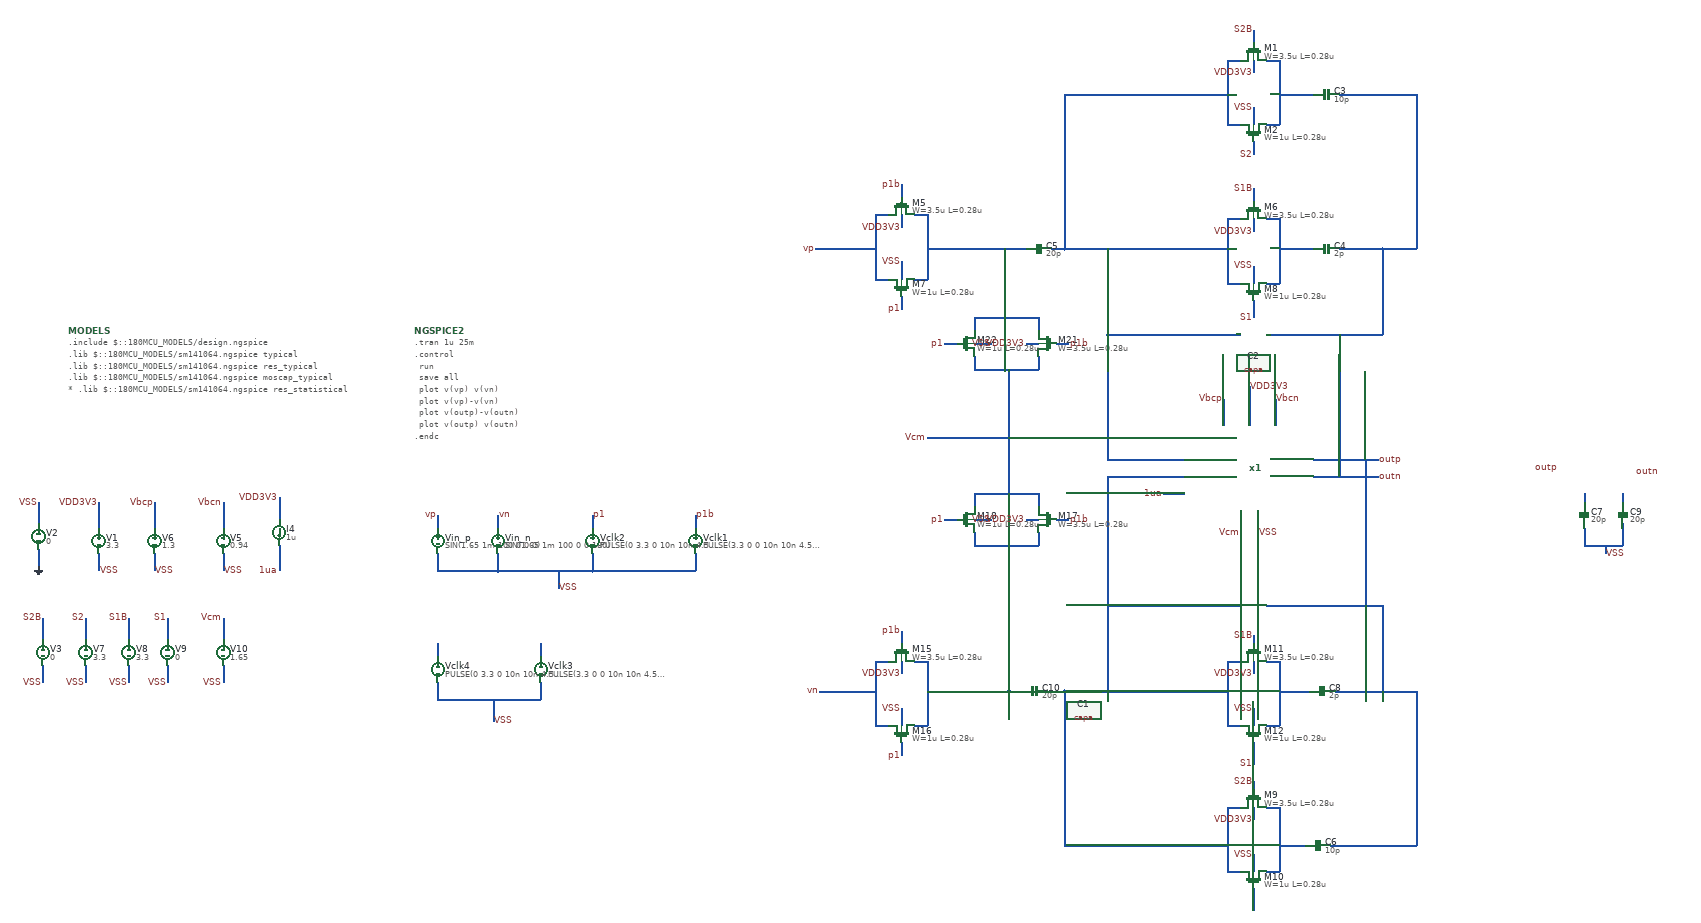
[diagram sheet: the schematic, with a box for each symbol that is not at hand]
v {xschem version=3.4.8RC file_version=1.3}
G {}
K {}
V {}
S {}
F {}
E {}
N 1350 -1840 1350 -1790 {lab=VDD3V3}
N 1350 -1730 1350 -1670 {lab=1ua}
N 1220 -1710 1220 -1670 {lab=VSS}
N 1220 -1830 1220 -1770 {lab=Vbcn}
N 1060 -1710 1060 -1670 {lab=VSS}
N 1060 -1830 1060 -1770 {lab=Vbcp}
N 930 -1710 930 -1670 {lab=VSS}
N 930 -1830 930 -1770 {lab=VDD3V3}
N 790 -1720 790 -1690 {lab=0}
N 790 -1690 790 -1680 {lab=0}
N 790 -1830 790 -1780 {lab=VSS}
N 3630 -1810 3630 -1760 {lab=VSS}
N 3190 -2420 3320 -2420 {lab=#net1}
N 3380 -2420 3560 -2420 {lab=#net1}
N 3180 -2420 3190 -2420 {lab=#net1}
N 3280 -2220 3590 -2220 {lab=#net1}
N 3280 -2420 3280 -2220 {lab=#net1}
N 3650 -2220 3920 -2220 {lab=outn}
N 3920 -2420 3920 -2220 {lab=outn}
N 3190 -2780 3320 -2780 {lab=#net1}
N 3180 -2780 3190 -2780 {lab=#net1}
N 3180 -2780 3180 -2420 {lab=#net1}
N 4000 -2780 4000 -2420 {lab=outn}
N 3760 -1930 3910 -1930 {lab=outp}
N 2610 -2420 2740 -2420 {lab=vp}
N 2600 -2420 2610 -2420 {lab=vp}
N 3190 -1390 3320 -1390 {lab=#net2}
N 3380 -1390 3560 -1390 {lab=#net2}
N 3180 -1390 3190 -1390 {lab=#net2}
N 3280 -1590 3590 -1590 {lab=#net2}
N 3280 -1590 3280 -1390 {lab=#net2}
N 3650 -1590 3920 -1590 {lab=outp}
N 3920 -1590 3920 -1390 {lab=outp}
N 3190 -1030 3320 -1030 {lab=#net2}
N 3380 -1030 3560 -1030 {lab=#net2}
N 3180 -1030 3190 -1030 {lab=#net2}
N 3180 -1390 3180 -1030 {lab=#net2}
N 4000 -1390 4000 -1030 {lab=outp}
N 2610 -1390 2740 -1390 {lab=vn}
N 3760 -1890 3910 -1890 {lab=outn}
N 2860 -2420 2930 -2420 {lab=#net3}
N 3040 -2420 3040 -2260 {lab=#net3}
N 3050 -1730 3050 -1570 {lab=#net4}
N 3050 -2140 3050 -1930 {lab=Vcm}
N 3050 -1930 3050 -1850 {lab=Vcm}
N 2860 -1980 3050 -1980 {lab=Vcm}
N 2860 -1390 2920 -1390 {lab=#net4}
N 3050 -1570 3050 -1390 {lab=#net4}
N 3280 -2220 3280 -1930 {lab=#net1}
N 3320 -2780 3560 -2780 {lab=#net1}
N 3680 -2780 3760 -2780 {lab=#net5}
N 3820 -2780 4000 -2780 {lab=outn}
N 3680 -2420 3760 -2420 {lab=#net6}
N 3820 -2420 3920 -2420 {lab=outn}
N 3920 -2420 4000 -2420 {lab=outn}
N 3320 -2420 3380 -2420 {lab=#net1}
N 3820 -2220 3820 -1890 {lab=outn}
N 3880 -1920 3880 -1590 {lab=outp}
N 2930 -2420 3050 -2420 {lab=#net3}
N 3050 -2420 3090 -2420 {lab=#net3}
N 3150 -2420 3180 -2420 {lab=#net1}
N 3140 -1390 3180 -1390 {lab=#net2}
N 3050 -1390 3080 -1390 {lab=#net4}
N 2920 -1390 3050 -1390 {lab=#net4}
N 3560 -2860 3590 -2860 {lab=#net1}
N 3560 -2860 3560 -2710 {lab=#net1}
N 3560 -2710 3590 -2710 {lab=#net1}
N 3650 -2860 3680 -2860 {lab=#net5}
N 3680 -2860 3680 -2710 {lab=#net5}
N 3650 -2710 3680 -2710 {lab=#net5}
N 3280 -1890 3280 -1590 {lab=#net2}
N 3880 -1930 3880 -1920 {lab=outp}
N 3320 -1390 3380 -1390 {lab=#net2}
N 3810 -1390 4000 -1390 {lab=outp}
N 3680 -1390 3750 -1390 {lab=#net7}
N 3800 -1030 3990 -1030 {lab=outp}
N 3990 -1030 4000 -1030 {lab=outp}
N 3320 -1030 3380 -1030 {lab=#net2}
N 3620 -2860 3620 -2830 {lab=VDD3V3}
N 3620 -2750 3620 -2710 {lab=VSS}
N 3560 -2490 3590 -2490 {lab=#net1}
N 3560 -2490 3560 -2340 {lab=#net1}
N 3560 -2340 3590 -2340 {lab=#net1}
N 3650 -2490 3680 -2490 {lab=#net6}
N 3680 -2490 3680 -2340 {lab=#net6}
N 3650 -2340 3680 -2340 {lab=#net6}
N 3620 -2490 3620 -2460 {lab=VDD3V3}
N 3620 -2380 3620 -2340 {lab=VSS}
N 3560 -1120 3590 -1120 {lab=#net2}
N 3560 -1120 3560 -970 {lab=#net2}
N 3560 -970 3590 -970 {lab=#net2}
N 3650 -1120 3680 -1120 {lab=#net8}
N 3680 -1120 3680 -970 {lab=#net8}
N 3650 -970 3680 -970 {lab=#net8}
N 3620 -1120 3620 -1090 {lab=VDD3V3}
N 3620 -1010 3620 -970 {lab=VSS}
N 3560 -1460 3590 -1460 {lab=#net2}
N 3560 -1460 3560 -1310 {lab=#net2}
N 3560 -1310 3590 -1310 {lab=#net2}
N 3650 -1460 3680 -1460 {lab=#net7}
N 3680 -1460 3680 -1310 {lab=#net7}
N 3650 -1310 3680 -1310 {lab=#net7}
N 3620 -1460 3620 -1430 {lab=VDD3V3}
N 3620 -1350 3620 -1310 {lab=VSS}
N 2740 -2500 2770 -2500 {lab=vp}
N 2740 -2500 2740 -2350 {lab=vp}
N 2740 -2350 2770 -2350 {lab=vp}
N 2830 -2500 2860 -2500 {lab=#net3}
N 2860 -2500 2860 -2350 {lab=#net3}
N 2830 -2350 2860 -2350 {lab=#net3}
N 2800 -2500 2800 -2470 {lab=VDD3V3}
N 2800 -2390 2800 -2350 {lab=VSS}
N 2740 -1460 2770 -1460 {lab=vn}
N 2740 -1460 2740 -1310 {lab=vn}
N 2740 -1310 2770 -1310 {lab=vn}
N 2830 -1460 2860 -1460 {lab=#net4}
N 2860 -1460 2860 -1310 {lab=#net4}
N 2830 -1310 2860 -1310 {lab=#net4}
N 2800 -1460 2800 -1430 {lab=VDD3V3}
N 2800 -1350 2800 -1310 {lab=VSS}
N 3120 -2260 3120 -2230 {lab=#net3}
N 2970 -2260 3120 -2260 {lab=#net3}
N 2970 -2260 2970 -2230 {lab=#net3}
N 3120 -2170 3120 -2140 {lab=Vcm}
N 2970 -2140 3120 -2140 {lab=Vcm}
N 2970 -2170 2970 -2140 {lab=Vcm}
N 3090 -2200 3120 -2200 {lab=VDD3V3}
N 2970 -2200 3010 -2200 {lab=VSS}
N 3120 -1850 3120 -1820 {lab=Vcm}
N 2970 -1850 3120 -1850 {lab=Vcm}
N 2970 -1850 2970 -1820 {lab=Vcm}
N 3120 -1760 3120 -1730 {lab=#net4}
N 2970 -1730 3120 -1730 {lab=#net4}
N 2970 -1760 2970 -1730 {lab=#net4}
N 3090 -1790 3120 -1790 {lab=VDD3V3}
N 2970 -1790 3010 -1790 {lab=VSS}
N 1720 -1710 1720 -1670 {lab=VSS}
N 1860 -1710 1860 -1670 {lab=VSS}
N 1720 -1670 1860 -1670 {lab=VSS}
N 2000 -1670 2000 -1630 {lab=VSS}
N 1720 -1800 1720 -1770 {lab=vp}
N 1860 -1800 1860 -1770 {lab=vn}
N 3620 -2930 3620 -2900 {lab=S2B}
N 3620 -2670 3620 -2640 {lab=S2}
N 3620 -2560 3620 -2530 {lab=S1B}
N 3620 -2300 3620 -2270 {lab=S1}
N 3620 -2270 3620 -2260 {lab=S1}
N 3620 -1520 3620 -1500 {lab=S1B}
N 3620 -1270 3620 -1220 {lab=S1}
N 3620 -1180 3620 -1160 {lab=S2B}
N 3620 -930 3620 -880 {lab=#net9}
N 3680 -1030 3740 -1030 {lab=#net8}
N 2800 -2570 2800 -2540 {lab=p1b}
N 2800 -2310 2800 -2280 {lab=p1}
N 2800 -1530 2800 -1500 {lab=p1b}
N 2800 -1270 2800 -1240 {lab=p1}
N 2900 -1790 2930 -1790 {lab=p1}
N 3160 -1790 3190 -1790 {lab=p1b}
N 3160 -2200 3190 -2200 {lab=p1b}
N 2900 -2200 2930 -2200 {lab=p1}
N 2080 -1710 2080 -1670 {lab=VSS}
N 2080 -1800 2080 -1770 {lab=p1}
N 1860 -1670 2080 -1670 {lab=VSS}
N 2320 -1710 2320 -1670 {lab=VSS}
N 2320 -1800 2320 -1770 {lab=p1b}
N 2080 -1670 2320 -1670 {lab=VSS}
N 800 -1450 800 -1420 {lab=VSS}
N 800 -1420 800 -1410 {lab=VSS}
N 800 -1560 800 -1510 {lab=S2B}
N 900 -1450 900 -1420 {lab=VSS}
N 900 -1420 900 -1410 {lab=VSS}
N 900 -1560 900 -1510 {lab=S2}
N 1000 -1450 1000 -1420 {lab=VSS}
N 1000 -1420 1000 -1410 {lab=VSS}
N 1000 -1560 1000 -1510 {lab=S1B}
N 1090 -1450 1090 -1420 {lab=VSS}
N 1090 -1420 1090 -1410 {lab=VSS}
N 1090 -1560 1090 -1510 {lab=S1}
N 3280 -1930 3460 -1930 {lab=#net1}
N 3280 -1890 3460 -1890 {lab=#net2}
N 3410 -1850 3460 -1850 {lab=1ua}
N 3610 -2100 3610 -2010 {lab=VDD3V3}
N 3670 -2070 3670 -2010 {lab=Vbcn}
N 3590 -1810 3590 -1760 {lab=Vcm}
N 1220 -1450 1220 -1420 {lab=VSS}
N 1220 -1420 1220 -1410 {lab=VSS}
N 1220 -1560 1220 -1510 {lab=Vcm}
N 4390 -1850 4390 -1830 {lab=#net10}
N 4480 -1850 4480 -1830 {lab=#net11}
N 4390 -1770 4390 -1730 {lab=VSS}
N 4390 -1730 4480 -1730 {lab=VSS}
N 4480 -1780 4480 -1730 {lab=VSS}
N 4440 -1730 4440 -1710 {lab=VSS}
N 3550 -2070 3550 -2010 {lab=Vbcp}
N 1720 -1410 1720 -1370 {lab=VSS}
N 1720 -1500 1720 -1470 {lab=#net12}
N 1960 -1410 1960 -1370 {lab=VSS}
N 1960 -1500 1960 -1470 {lab=#net13}
N 1720 -1370 1960 -1370 {lab=VSS}
N 1850 -1370 1850 -1320 {lab=VSS}
C {isource.sym} 1350 -1760 0 0 {name=I4 value=1u}
C {lab_pin.sym} 1350 -1670 0 0 {name=p61 sig_type=std_logic lab=1ua}
C {vsource.sym} 1220 -1740 0 0 {name=V5 value=0.94 savecurrent=false}
C {vsource.sym} 1060 -1740 0 0 {name=V6 value=1.3 savecurrent=false}
C {lab_pin.sym} 1060 -1830 0 0 {name=p24 sig_type=std_logic lab=Vbcp}
C {lab_pin.sym} 1220 -1830 0 0 {name=p12 sig_type=std_logic lab=Vbcn}
C {lab_wire.sym} 1060 -1670 0 1 {name=p32 sig_type=std_logic lab=VSS}
C {lab_wire.sym} 1220 -1670 0 1 {name=p43 sig_type=std_logic lab=VSS}
C {vsource.sym} 930 -1740 0 0 {name=V1 value=3.3 savecurrent=false}
C {lab_pin.sym} 930 -1830 0 0 {name=p5 sig_type=std_logic lab=VDD3V3}
C {lab_wire.sym} 790 -1830 0 0 {name=p15 sig_type=std_logic lab=VSS}
C {vsource.sym} 790 -1750 0 0 {name=V2 value=0 savecurrent=false}
C {lab_wire.sym} 930 -1670 0 1 {name=p42 sig_type=std_logic lab=VSS}
C {gnd.sym} 790 -1680 0 0 {name=l1 lab=0}
C {lab_pin.sym} 1350 -1840 0 0 {name=p1 sig_type=std_logic lab=VDD3V3}
C {lab_pin.sym} 3410 -1850 0 0 {name=p2 sig_type=std_logic lab=1ua}
C {lab_wire.sym} 3630 -1760 0 1 {name=p3 sig_type=std_logic lab=VSS}
C {lab_pin.sym} 3610 -2100 0 1 {name=p4 sig_type=std_logic lab=VDD3V3}
C {capa.sym} 3790 -2780 3 1 {name=C3
m=1
value=10p
footprint=1206
device="ceramic capacitor"}
C {capa.sym} 3120 -2420 1 0 {name=C5
m=1
value=20p
footprint=1206
device="ceramic capacitor"}
C {capa.sym} 3110 -1390 1 1 {name=C10
m=1
value=20p
footprint=1206
device="ceramic capacitor"}
C {lab_pin.sym} 3910 -1930 0 1 {name=p11 sig_type=std_logic lab=outp}
C {lab_pin.sym} 3910 -1890 0 1 {name=p13 sig_type=std_logic lab=outn}
C {capa.sym} 3790 -2420 3 1 {name=C4
m=1
value=2p
footprint=1206
device="ceramic capacitor"}
C {lab_wire.sym} 2600 -2420 0 0 {name=p14 sig_type=std_logic lab=vp}
C {lab_wire.sym} 2610 -1390 0 0 {name=p16 sig_type=std_logic lab=vn}
C {symbols/pfet_03v3.sym} 3620 -2880 1 0 {name=M1
L=0.28u
W=3.5u
nf=1
m=1
ad="'int((nf+1)/2) * W/nf * 0.18u'"
pd="'2*int((nf+1)/2) * (W/nf + 0.18u)'"
as="'int((nf+2)/2) * W/nf * 0.18u'"
ps="'2*int((nf+2)/2) * (W/nf + 0.18u)'"
nrd="'0.18u / W'" nrs="'0.18u / W'"
sa=0 sb=0 sd=0
model=pfet_03v3
spiceprefix=X
}
C {symbols/nfet_03v3.sym} 3620 -2690 1 1 {name=M2
L=0.28u
W=1u
nf=1
m=1
ad="'int((nf+1)/2) * W/nf * 0.18u'"
pd="'2*int((nf+1)/2) * (W/nf + 0.18u)'"
as="'int((nf+2)/2) * W/nf * 0.18u'"
ps="'2*int((nf+2)/2) * (W/nf + 0.18u)'"
nrd="'0.18u / W'" nrs="'0.18u / W'"
sa=0 sb=0 sd=0
model=nfet_03v3
spiceprefix=X
}
C {capa.sym} 3520 -1550 3 1 {name=C1
m=1
value=1p
footprint=1206
device="ceramic capacitor"}
C {capa.sym} 3770 -1030 3 1 {name=C6
m=1
value=10p
footprint=1206
device="ceramic capacitor"}
C {lab_pin.sym} 3620 -2830 0 0 {name=p17 sig_type=std_logic lab=VDD3V3}
C {lab_wire.sym} 3620 -2750 0 0 {name=p18 sig_type=std_logic lab=VSS}
C {symbols/pfet_03v3.sym} 3620 -2510 1 0 {name=M6
L=0.28u
W=3.5u
nf=1
m=1
ad="'int((nf+1)/2) * W/nf * 0.18u'"
pd="'2*int((nf+1)/2) * (W/nf + 0.18u)'"
as="'int((nf+2)/2) * W/nf * 0.18u'"
ps="'2*int((nf+2)/2) * (W/nf + 0.18u)'"
nrd="'0.18u / W'" nrs="'0.18u / W'"
sa=0 sb=0 sd=0
model=pfet_03v3
spiceprefix=X
}
C {symbols/nfet_03v3.sym} 3620 -2320 1 1 {name=M8
L=0.28u
W=1u
nf=1
m=1
ad="'int((nf+1)/2) * W/nf * 0.18u'"
pd="'2*int((nf+1)/2) * (W/nf + 0.18u)'"
as="'int((nf+2)/2) * W/nf * 0.18u'"
ps="'2*int((nf+2)/2) * (W/nf + 0.18u)'"
nrd="'0.18u / W'" nrs="'0.18u / W'"
sa=0 sb=0 sd=0
model=nfet_03v3
spiceprefix=X
}
C {lab_pin.sym} 3620 -2460 0 0 {name=p21 sig_type=std_logic lab=VDD3V3}
C {lab_wire.sym} 3620 -2380 0 0 {name=p22 sig_type=std_logic lab=VSS}
C {symbols/pfet_03v3.sym} 3620 -1140 1 0 {name=M9
L=0.28u
W=3.5u
nf=1
m=1
ad="'int((nf+1)/2) * W/nf * 0.18u'"
pd="'2*int((nf+1)/2) * (W/nf + 0.18u)'"
as="'int((nf+2)/2) * W/nf * 0.18u'"
ps="'2*int((nf+2)/2) * (W/nf + 0.18u)'"
nrd="'0.18u / W'" nrs="'0.18u / W'"
sa=0 sb=0 sd=0
model=pfet_03v3
spiceprefix=X
}
C {symbols/nfet_03v3.sym} 3620 -950 1 1 {name=M10
L=0.28u
W=1u
nf=1
m=1
ad="'int((nf+1)/2) * W/nf * 0.18u'"
pd="'2*int((nf+1)/2) * (W/nf + 0.18u)'"
as="'int((nf+2)/2) * W/nf * 0.18u'"
ps="'2*int((nf+2)/2) * (W/nf + 0.18u)'"
nrd="'0.18u / W'" nrs="'0.18u / W'"
sa=0 sb=0 sd=0
model=nfet_03v3
spiceprefix=X
}
C {lab_pin.sym} 3620 -1090 0 0 {name=p23 sig_type=std_logic lab=VDD3V3}
C {lab_wire.sym} 3620 -1010 0 0 {name=p25 sig_type=std_logic lab=VSS}
C {symbols/pfet_03v3.sym} 3620 -1480 1 0 {name=M11
L=0.28u
W=3.5u
nf=1
m=1
ad="'int((nf+1)/2) * W/nf * 0.18u'"
pd="'2*int((nf+1)/2) * (W/nf + 0.18u)'"
as="'int((nf+2)/2) * W/nf * 0.18u'"
ps="'2*int((nf+2)/2) * (W/nf + 0.18u)'"
nrd="'0.18u / W'" nrs="'0.18u / W'"
sa=0 sb=0 sd=0
model=pfet_03v3
spiceprefix=X
}
C {symbols/nfet_03v3.sym} 3620 -1290 1 1 {name=M12
L=0.28u
W=1u
nf=1
m=1
ad="'int((nf+1)/2) * W/nf * 0.18u'"
pd="'2*int((nf+1)/2) * (W/nf + 0.18u)'"
as="'int((nf+2)/2) * W/nf * 0.18u'"
ps="'2*int((nf+2)/2) * (W/nf + 0.18u)'"
nrd="'0.18u / W'" nrs="'0.18u / W'"
sa=0 sb=0 sd=0
model=nfet_03v3
spiceprefix=X
}
C {lab_pin.sym} 3620 -1430 0 0 {name=p26 sig_type=std_logic lab=VDD3V3}
C {lab_wire.sym} 3620 -1350 0 0 {name=p27 sig_type=std_logic lab=VSS}
C {symbols/pfet_03v3.sym} 2800 -2520 1 0 {name=M5
L=0.28u
W=3.5u
nf=1
m=1
ad="'int((nf+1)/2) * W/nf * 0.18u'"
pd="'2*int((nf+1)/2) * (W/nf + 0.18u)'"
as="'int((nf+2)/2) * W/nf * 0.18u'"
ps="'2*int((nf+2)/2) * (W/nf + 0.18u)'"
nrd="'0.18u / W'" nrs="'0.18u / W'"
sa=0 sb=0 sd=0
model=pfet_03v3
spiceprefix=X
}
C {symbols/nfet_03v3.sym} 2800 -2330 1 1 {name=M7
L=0.28u
W=1u
nf=1
m=1
ad="'int((nf+1)/2) * W/nf * 0.18u'"
pd="'2*int((nf+1)/2) * (W/nf + 0.18u)'"
as="'int((nf+2)/2) * W/nf * 0.18u'"
ps="'2*int((nf+2)/2) * (W/nf + 0.18u)'"
nrd="'0.18u / W'" nrs="'0.18u / W'"
sa=0 sb=0 sd=0
model=nfet_03v3
spiceprefix=X
}
C {lab_pin.sym} 2800 -2470 0 0 {name=p30 sig_type=std_logic lab=VDD3V3}
C {lab_wire.sym} 2800 -2390 0 0 {name=p31 sig_type=std_logic lab=VSS}
C {symbols/pfet_03v3.sym} 2800 -1480 1 0 {name=M15
L=0.28u
W=3.5u
nf=1
m=1
ad="'int((nf+1)/2) * W/nf * 0.18u'"
pd="'2*int((nf+1)/2) * (W/nf + 0.18u)'"
as="'int((nf+2)/2) * W/nf * 0.18u'"
ps="'2*int((nf+2)/2) * (W/nf + 0.18u)'"
nrd="'0.18u / W'" nrs="'0.18u / W'"
sa=0 sb=0 sd=0
model=pfet_03v3
spiceprefix=X
}
C {symbols/nfet_03v3.sym} 2800 -1290 1 1 {name=M16
L=0.28u
W=1u
nf=1
m=1
ad="'int((nf+1)/2) * W/nf * 0.18u'"
pd="'2*int((nf+1)/2) * (W/nf + 0.18u)'"
as="'int((nf+2)/2) * W/nf * 0.18u'"
ps="'2*int((nf+2)/2) * (W/nf + 0.18u)'"
nrd="'0.18u / W'" nrs="'0.18u / W'"
sa=0 sb=0 sd=0
model=nfet_03v3
spiceprefix=X
}
C {lab_pin.sym} 2800 -1430 0 0 {name=p33 sig_type=std_logic lab=VDD3V3}
C {lab_wire.sym} 2800 -1350 0 0 {name=p34 sig_type=std_logic lab=VSS}
C {symbols/pfet_03v3.sym} 3140 -2200 2 0 {name=M21
L=0.28u
W=3.5u
nf=1
m=1
ad="'int((nf+1)/2) * W/nf * 0.18u'"
pd="'2*int((nf+1)/2) * (W/nf + 0.18u)'"
as="'int((nf+2)/2) * W/nf * 0.18u'"
ps="'2*int((nf+2)/2) * (W/nf + 0.18u)'"
nrd="'0.18u / W'" nrs="'0.18u / W'"
sa=0 sb=0 sd=0
model=pfet_03v3
spiceprefix=X
}
C {symbols/nfet_03v3.sym} 2950 -2200 2 1 {name=M22
L=0.28u
W=1u
nf=1
m=1
ad="'int((nf+1)/2) * W/nf * 0.18u'"
pd="'2*int((nf+1)/2) * (W/nf + 0.18u)'"
as="'int((nf+2)/2) * W/nf * 0.18u'"
ps="'2*int((nf+2)/2) * (W/nf + 0.18u)'"
nrd="'0.18u / W'" nrs="'0.18u / W'"
sa=0 sb=0 sd=0
model=nfet_03v3
spiceprefix=X
}
C {lab_pin.sym} 3090 -2200 1 0 {name=p35 sig_type=std_logic lab=VDD3V3}
C {lab_wire.sym} 3010 -2200 1 0 {name=p36 sig_type=std_logic lab=VSS}
C {symbols/pfet_03v3.sym} 3140 -1790 2 0 {name=M17
L=0.28u
W=3.5u
nf=1
m=1
ad="'int((nf+1)/2) * W/nf * 0.18u'"
pd="'2*int((nf+1)/2) * (W/nf + 0.18u)'"
as="'int((nf+2)/2) * W/nf * 0.18u'"
ps="'2*int((nf+2)/2) * (W/nf + 0.18u)'"
nrd="'0.18u / W'" nrs="'0.18u / W'"
sa=0 sb=0 sd=0
model=pfet_03v3
spiceprefix=X
}
C {symbols/nfet_03v3.sym} 2950 -1790 2 1 {name=M18
L=0.28u
W=1u
nf=1
m=1
ad="'int((nf+1)/2) * W/nf * 0.18u'"
pd="'2*int((nf+1)/2) * (W/nf + 0.18u)'"
as="'int((nf+2)/2) * W/nf * 0.18u'"
ps="'2*int((nf+2)/2) * (W/nf + 0.18u)'"
nrd="'0.18u / W'" nrs="'0.18u / W'"
sa=0 sb=0 sd=0
model=nfet_03v3
spiceprefix=X
}
C {lab_pin.sym} 3090 -1790 1 0 {name=p37 sig_type=std_logic lab=VDD3V3}
C {lab_wire.sym} 3010 -1790 1 0 {name=p38 sig_type=std_logic lab=VSS}
C {lab_pin.sym} 1720 -1800 0 0 {name=p71 sig_type=std_logic lab=vp}
C {lab_pin.sym} 1860 -1800 0 1 {name=p75 sig_type=std_logic lab=vn}
C {vsource.sym} 1720 -1740 0 1 {name=Vin_p value="SIN(1.65 1m 100 0 0 0)" savecurrent=false}
C {vsource.sym} 1860 -1740 0 0 {name=Vin_n value="SIN(1.65 1m 100 0 0 180)" savecurrent=false}
C {lab_wire.sym} 2000 -1630 0 1 {name=p80 sig_type=std_logic lab=VSS}
C {devices/code_shown.sym} 1665.119489031288 -2230 0 0 {name=NGSPICE2 only_toplevel=true
value="
.tran 1u 25m

.control
  run
  save all
  plot v(vp) v(vn)
  plot v(vp)-v(vn)
  plot v(outp)-v(outn)
  plot v(outp) v(outn)
.endc
"}
C {lab_wire.sym} 3620 -2640 0 0 {name=p39 sig_type=std_logic lab=S2}
C {lab_wire.sym} 3620 -2930 0 0 {name=p44 sig_type=std_logic lab=S2B}
C {lab_wire.sym} 3620 -2260 0 0 {name=p45 sig_type=std_logic lab=S1}
C {lab_wire.sym} 3620 -2560 0 0 {name=p46 sig_type=std_logic lab=S1B}
C {lab_wire.sym} 3620 -1220 0 0 {name=p47 sig_type=std_logic lab=S1}
C {lab_wire.sym} 3620 -1520 0 0 {name=p48 sig_type=std_logic lab=S1B}
C {lab_wire.sym} 3620 -1180 0 0 {name=p50 sig_type=std_logic lab=S2B}
C {lab_wire.sym} 2800 -2280 0 0 {name=p53 sig_type=std_logic lab=p1}
C {lab_wire.sym} 2800 -2570 0 0 {name=p54 sig_type=std_logic lab=p1b}
C {lab_wire.sym} 2800 -1240 0 0 {name=p55 sig_type=std_logic lab=p1}
C {lab_wire.sym} 2800 -1530 0 0 {name=p56 sig_type=std_logic lab=p1b}
C {lab_wire.sym} 3190 -1790 0 1 {name=p57 sig_type=std_logic lab=p1b}
C {lab_wire.sym} 2900 -1790 0 0 {name=p58 sig_type=std_logic lab=p1}
C {lab_wire.sym} 3190 -2200 0 1 {name=p59 sig_type=std_logic lab=p1b}
C {lab_wire.sym} 2900 -2200 0 0 {name=p60 sig_type=std_logic lab=p1}
C {lab_pin.sym} 2080 -1800 0 1 {name=p62 sig_type=std_logic lab=p1}
C {vsource.sym} 2320 -1740 0 0 {name=Vclk1 value="PULSE(3.3 0 0 10n 10n 4.5u 10u)" savecurrent=false}
C {lab_pin.sym} 2320 -1800 0 1 {name=p63 sig_type=std_logic lab=p1b}
C {vsource.sym} 2080 -1740 0 0 {name=Vclk2 value="PULSE(0 3.3 0 10n 10n 4.5u 10u)" savecurrent=false}
C {lab_wire.sym} 800 -1410 0 0 {name=p64 sig_type=std_logic lab=VSS}
C {lab_wire.sym} 800 -1560 0 0 {name=p65 sig_type=std_logic lab=S2B}
C {lab_wire.sym} 900 -1410 0 0 {name=p66 sig_type=std_logic lab=VSS}
C {vsource.sym} 900 -1480 0 0 {name=V7 value=3.3 savecurrent=false}
C {lab_wire.sym} 900 -1560 0 0 {name=p67 sig_type=std_logic lab=S2}
C {lab_wire.sym} 1000 -1410 0 0 {name=p68 sig_type=std_logic lab=VSS}
C {vsource.sym} 1000 -1480 0 0 {name=V8 value=3.3 savecurrent=false}
C {lab_wire.sym} 1000 -1560 0 0 {name=p69 sig_type=std_logic lab=S1B}
C {lab_wire.sym} 1090 -1410 0 0 {name=p70 sig_type=std_logic lab=VSS}
C {vsource.sym} 1090 -1480 0 0 {name=V9 value=0 savecurrent=false}
C {lab_wire.sym} 1090 -1560 0 0 {name=p72 sig_type=std_logic lab=S1}
C {/foss/designs/folded_cascode/folded_cascode_v2.sym} 3610 -1910 0 0 {name=x1}
C {lab_wire.sym} 3590 -1760 0 0 {name=p73 sig_type=std_logic lab=Vcm}
C {lab_wire.sym} 1220 -1560 0 0 {name=p74 sig_type=std_logic lab=Vcm}
C {lab_wire.sym} 1220 -1410 0 0 {name=p76 sig_type=std_logic lab=VSS}
C {vsource.sym} 1220 -1480 0 0 {name=V10 value=1.65 savecurrent=false}
C {lab_pin.sym} 3550 -2070 0 0 {name=p77 sig_type=std_logic lab=Vbcp}
C {lab_pin.sym} 3670 -2070 0 1 {name=p6 sig_type=std_logic lab=Vbcn}
C {devices/code_shown.sym} 860 -2230 0 0 {name=MODELS only_toplevel=true
format="tcleval( @value )"
value="
.include $::180MCU_MODELS/design.ngspice
.lib $::180MCU_MODELS/sm141064.ngspice typical
.lib $::180MCU_MODELS/sm141064.ngspice res_typical
.lib $::180MCU_MODELS/sm141064.ngspice moscap_typical
* .lib $::180MCU_MODELS/sm141064.ngspice res_statistical
"}
C {capa.sym} 4390 -1800 0 0 {name=C7
m=1
value=20p
footprint=1206
device="ceramic capacitor"}
C {lab_wire.sym} 4440 -1710 0 1 {name=p7 sig_type=std_logic lab=VSS}
C {capa.sym} 4480 -1800 0 0 {name=C9
m=1
value=20p
footprint=1206
device="ceramic capacitor"}
C {lab_pin.sym} 4330 -1910 0 0 {name=p78 sig_type=std_logic lab=outp}
C {lab_pin.sym} 4510 -1900 0 1 {name=p79 sig_type=std_logic lab=outn}
C {lab_wire.sym} 2860 -1980 0 0 {name=p8 sig_type=std_logic lab=Vcm}
C {vsource.sym} 800 -1480 0 0 {name=V3 value=0 savecurrent=false}
C {capa.sym} 3780 -1390 3 1 {name=C8
m=1
value=2p
footprint=1206
device="ceramic capacitor"}
C {capa.sym} 3620 -2190 3 1 {name=C2
m=1
value=1p
footprint=1206
device="ceramic capacitor"}
C {vsource.sym} 1960 -1440 0 0 {name=Vclk3 value="PULSE(3.3 0 0 10n 10n 4.5u 10u)" savecurrent=false}
C {vsource.sym} 1720 -1440 0 0 {name=Vclk4 value="PULSE(0 3.3 0 10n 10n 4.5u 10u)" savecurrent=false}
C {lab_wire.sym} 1850 -1320 0 1 {name=p19 sig_type=std_logic lab=VSS}
